VERSION 5.8 ;
BUSBITCHARS "[]" ;
DIVIDERCHAR "/" ;
UNITS
    DATABASE MICRONS 2000 ;
END UNITS

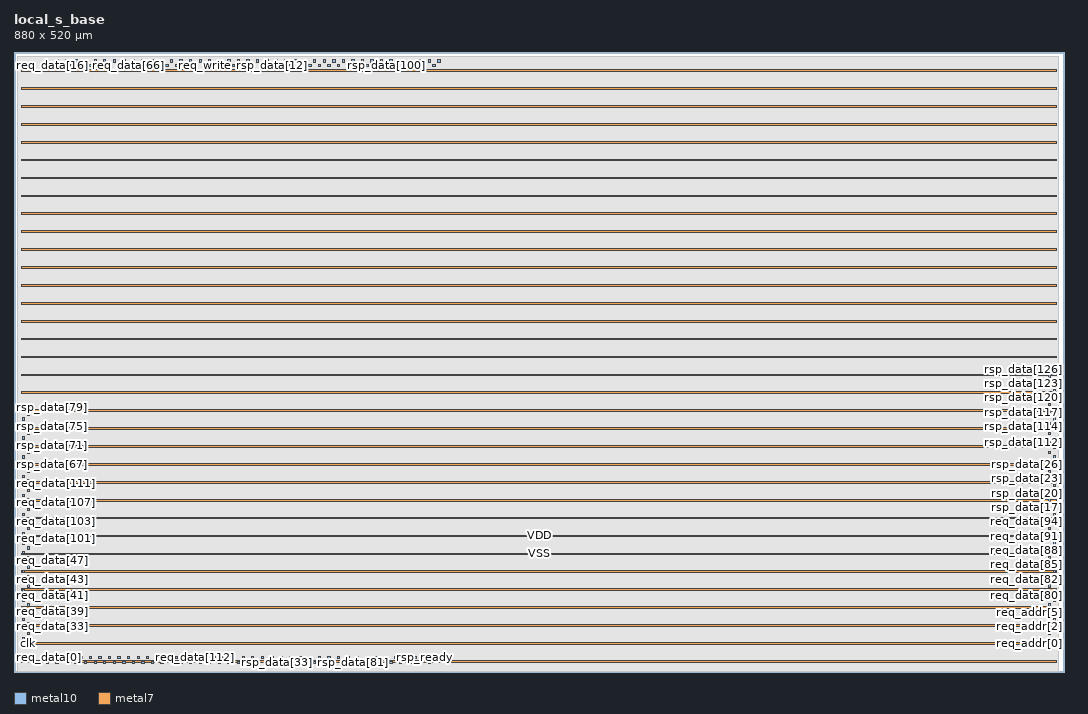
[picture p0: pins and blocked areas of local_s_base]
MACRO local_s_base
  FOREIGN local_s_base 0 0 ;
  CLASS BLOCK ;
  SIZE 880 BY 520 ;
  PIN clk
    DIRECTION INPUT ;
    USE SIGNAL ;
    PORT
      LAYER metal10 ;
        RECT  11.095 23.07 13.095 25.07 ;
    END
  END clk
  PIN req_addr[0]
    DIRECTION INPUT ;
    USE SIGNAL ;
    PORT
      LAYER metal10 ;
        RECT  867.095 23.07 869.095 25.07 ;
    END
  END req_addr[0]
  PIN req_addr[1]
    DIRECTION INPUT ;
    USE SIGNAL ;
    PORT
      LAYER metal10 ;
        RECT  871.095 27.07 873.095 29.07 ;
    END
  END req_addr[1]
  PIN req_addr[2]
    DIRECTION INPUT ;
    USE SIGNAL ;
    PORT
      LAYER metal10 ;
        RECT  867.095 31.07 869.095 33.07 ;
    END
  END req_addr[2]
  PIN req_addr[3]
    DIRECTION INPUT ;
    USE SIGNAL ;
    PORT
      LAYER metal10 ;
        RECT  871.095 35.07 873.095 37.07 ;
    END
  END req_addr[3]
  PIN req_addr[4]
    DIRECTION INPUT ;
    USE SIGNAL ;
    PORT
      LAYER metal10 ;
        RECT  867.095 39.07 869.095 41.07 ;
    END
  END req_addr[4]
  PIN req_addr[5]
    DIRECTION INPUT ;
    USE SIGNAL ;
    PORT
      LAYER metal10 ;
        RECT  871.095 43.07 873.095 45.07 ;
    END
  END req_addr[5]
  PIN req_addr[6]
    DIRECTION INPUT ;
    USE SIGNAL ;
    PORT
      LAYER metal10 ;
        RECT  867.095 47.07 869.095 49.07 ;
    END
  END req_addr[6]
  PIN req_addr[7]
    DIRECTION INPUT ;
    USE SIGNAL ;
    PORT
      LAYER metal10 ;
        RECT  871.095 51.07 873.095 53.07 ;
    END
  END req_addr[7]
  PIN req_addr[8]
    DIRECTION INPUT ;
    USE SIGNAL ;
    PORT
      LAYER metal10 ;
        RECT  867.095 55.07 869.095 57.07 ;
    END
  END req_addr[8]
  PIN req_addr[9]
    DIRECTION INPUT ;
    USE SIGNAL ;
    PORT
      LAYER metal10 ;
        RECT  871.095 59.07 873.095 61.07 ;
    END
  END req_addr[9]
  PIN req_data[0]
    DIRECTION INPUT ;
    USE SIGNAL ;
    PORT
      LAYER metal10 ;
        RECT  23.095 11.07 25.095 13.07 ;
    END
  END req_data[0]
  PIN req_data[100]
    DIRECTION INPUT ;
    USE SIGNAL ;
    PORT
      LAYER metal10 ;
        RECT  7.095 107.07 9.095 109.07 ;
    END
  END req_data[100]
  PIN req_data[101]
    DIRECTION INPUT ;
    USE SIGNAL ;
    PORT
      LAYER metal10 ;
        RECT  11.095 111.07 13.095 113.07 ;
    END
  END req_data[101]
  PIN req_data[102]
    DIRECTION INPUT ;
    USE SIGNAL ;
    PORT
      LAYER metal10 ;
        RECT  7.095 115.07 9.095 117.07 ;
    END
  END req_data[102]
  PIN req_data[103]
    DIRECTION INPUT ;
    USE SIGNAL ;
    PORT
      LAYER metal10 ;
        RECT  11.095 119.07 13.095 121.07 ;
    END
  END req_data[103]
  PIN req_data[104]
    DIRECTION INPUT ;
    USE SIGNAL ;
    PORT
      LAYER metal10 ;
        RECT  7.095 123.07 9.095 125.07 ;
    END
  END req_data[104]
  PIN req_data[105]
    DIRECTION INPUT ;
    USE SIGNAL ;
    PORT
      LAYER metal10 ;
        RECT  11.095 127.07 13.095 129.07 ;
    END
  END req_data[105]
  PIN req_data[106]
    DIRECTION INPUT ;
    USE SIGNAL ;
    PORT
      LAYER metal10 ;
        RECT  7.095 131.07 9.095 133.07 ;
    END
  END req_data[106]
  PIN req_data[107]
    DIRECTION INPUT ;
    USE SIGNAL ;
    PORT
      LAYER metal10 ;
        RECT  11.095 135.07 13.095 137.07 ;
    END
  END req_data[107]
  PIN req_data[108]
    DIRECTION INPUT ;
    USE SIGNAL ;
    PORT
      LAYER metal10 ;
        RECT  7.095 139.07 9.095 141.07 ;
    END
  END req_data[108]
  PIN req_data[109]
    DIRECTION INPUT ;
    USE SIGNAL ;
    PORT
      LAYER metal10 ;
        RECT  11.095 143.07 13.095 145.07 ;
    END
  END req_data[109]
  PIN req_data[10]
    DIRECTION INPUT ;
    USE SIGNAL ;
    PORT
      LAYER metal10 ;
        RECT  63.095 11.07 65.095 13.07 ;
    END
  END req_data[10]
  PIN req_data[110]
    DIRECTION INPUT ;
    USE SIGNAL ;
    PORT
      LAYER metal10 ;
        RECT  7.095 147.07 9.095 149.07 ;
    END
  END req_data[110]
  PIN req_data[111]
    DIRECTION INPUT ;
    USE SIGNAL ;
    PORT
      LAYER metal10 ;
        RECT  11.095 151.07 13.095 153.07 ;
    END
  END req_data[111]
  PIN req_data[112]
    DIRECTION INPUT ;
    USE SIGNAL ;
    PORT
      LAYER metal10 ;
        RECT  151.095 11.07 153.095 13.07 ;
    END
  END req_data[112]
  PIN req_data[113]
    DIRECTION INPUT ;
    USE SIGNAL ;
    PORT
      LAYER metal10 ;
        RECT  155.095 7.07 157.095 9.07 ;
    END
  END req_data[113]
  PIN req_data[114]
    DIRECTION INPUT ;
    USE SIGNAL ;
    PORT
      LAYER metal10 ;
        RECT  159.095 11.07 161.095 13.07 ;
    END
  END req_data[114]
  PIN req_data[115]
    DIRECTION INPUT ;
    USE SIGNAL ;
    PORT
      LAYER metal10 ;
        RECT  163.095 7.07 165.095 9.07 ;
    END
  END req_data[115]
  PIN req_data[116]
    DIRECTION INPUT ;
    USE SIGNAL ;
    PORT
      LAYER metal10 ;
        RECT  167.095 11.07 169.095 13.07 ;
    END
  END req_data[116]
  PIN req_data[117]
    DIRECTION INPUT ;
    USE SIGNAL ;
    PORT
      LAYER metal10 ;
        RECT  171.095 7.07 173.095 9.07 ;
    END
  END req_data[117]
  PIN req_data[118]
    DIRECTION INPUT ;
    USE SIGNAL ;
    PORT
      LAYER metal10 ;
        RECT  175.095 11.07 177.095 13.07 ;
    END
  END req_data[118]
  PIN req_data[119]
    DIRECTION INPUT ;
    USE SIGNAL ;
    PORT
      LAYER metal10 ;
        RECT  179.095 7.07 181.095 9.07 ;
    END
  END req_data[119]
  PIN req_data[11]
    DIRECTION INPUT ;
    USE SIGNAL ;
    PORT
      LAYER metal10 ;
        RECT  67.095 7.07 69.095 9.07 ;
    END
  END req_data[11]
  PIN req_data[120]
    DIRECTION INPUT ;
    USE SIGNAL ;
    PORT
      LAYER metal10 ;
        RECT  183.095 11.07 185.095 13.07 ;
    END
  END req_data[120]
  PIN req_data[121]
    DIRECTION INPUT ;
    USE SIGNAL ;
    PORT
      LAYER metal10 ;
        RECT  187.095 7.07 189.095 9.07 ;
    END
  END req_data[121]
  PIN req_data[122]
    DIRECTION INPUT ;
    USE SIGNAL ;
    PORT
      LAYER metal10 ;
        RECT  191.095 11.07 193.095 13.07 ;
    END
  END req_data[122]
  PIN req_data[123]
    DIRECTION INPUT ;
    USE SIGNAL ;
    PORT
      LAYER metal10 ;
        RECT  195.095 7.07 197.095 9.07 ;
    END
  END req_data[123]
  PIN req_data[124]
    DIRECTION INPUT ;
    USE SIGNAL ;
    PORT
      LAYER metal10 ;
        RECT  199.095 11.07 201.095 13.07 ;
    END
  END req_data[124]
  PIN req_data[125]
    DIRECTION INPUT ;
    USE SIGNAL ;
    PORT
      LAYER metal10 ;
        RECT  203.095 7.07 205.095 9.07 ;
    END
  END req_data[125]
  PIN req_data[126]
    DIRECTION INPUT ;
    USE SIGNAL ;
    PORT
      LAYER metal10 ;
        RECT  207.095 11.07 209.095 13.07 ;
    END
  END req_data[126]
  PIN req_data[127]
    DIRECTION INPUT ;
    USE SIGNAL ;
    PORT
      LAYER metal10 ;
        RECT  211.095 7.07 213.095 9.07 ;
    END
  END req_data[127]
  PIN req_data[12]
    DIRECTION INPUT ;
    USE SIGNAL ;
    PORT
      LAYER metal10 ;
        RECT  71.095 11.07 73.095 13.07 ;
    END
  END req_data[12]
  PIN req_data[13]
    DIRECTION INPUT ;
    USE SIGNAL ;
    PORT
      LAYER metal10 ;
        RECT  75.095 7.07 77.095 9.07 ;
    END
  END req_data[13]
  PIN req_data[14]
    DIRECTION INPUT ;
    USE SIGNAL ;
    PORT
      LAYER metal10 ;
        RECT  79.095 11.07 81.095 13.07 ;
    END
  END req_data[14]
  PIN req_data[15]
    DIRECTION INPUT ;
    USE SIGNAL ;
    PORT
      LAYER metal10 ;
        RECT  83.095 7.07 85.095 9.07 ;
    END
  END req_data[15]
  PIN req_data[16]
    DIRECTION INPUT ;
    USE SIGNAL ;
    PORT
      LAYER metal10 ;
        RECT  23.095 507.07 25.095 509.07 ;
    END
  END req_data[16]
  PIN req_data[17]
    DIRECTION INPUT ;
    USE SIGNAL ;
    PORT
      LAYER metal10 ;
        RECT  27.095 511.07 29.095 513.07 ;
    END
  END req_data[17]
  PIN req_data[18]
    DIRECTION INPUT ;
    USE SIGNAL ;
    PORT
      LAYER metal10 ;
        RECT  31.095 507.07 33.095 509.07 ;
    END
  END req_data[18]
  PIN req_data[19]
    DIRECTION INPUT ;
    USE SIGNAL ;
    PORT
      LAYER metal10 ;
        RECT  35.095 511.07 37.095 513.07 ;
    END
  END req_data[19]
  PIN req_data[1]
    DIRECTION INPUT ;
    USE SIGNAL ;
    PORT
      LAYER metal10 ;
        RECT  27.095 7.07 29.095 9.07 ;
    END
  END req_data[1]
  PIN req_data[20]
    DIRECTION INPUT ;
    USE SIGNAL ;
    PORT
      LAYER metal10 ;
        RECT  39.095 507.07 41.095 509.07 ;
    END
  END req_data[20]
  PIN req_data[21]
    DIRECTION INPUT ;
    USE SIGNAL ;
    PORT
      LAYER metal10 ;
        RECT  43.095 511.07 45.095 513.07 ;
    END
  END req_data[21]
  PIN req_data[22]
    DIRECTION INPUT ;
    USE SIGNAL ;
    PORT
      LAYER metal10 ;
        RECT  47.095 507.07 49.095 509.07 ;
    END
  END req_data[22]
  PIN req_data[23]
    DIRECTION INPUT ;
    USE SIGNAL ;
    PORT
      LAYER metal10 ;
        RECT  51.095 511.07 53.095 513.07 ;
    END
  END req_data[23]
  PIN req_data[24]
    DIRECTION INPUT ;
    USE SIGNAL ;
    PORT
      LAYER metal10 ;
        RECT  55.095 507.07 57.095 509.07 ;
    END
  END req_data[24]
  PIN req_data[25]
    DIRECTION INPUT ;
    USE SIGNAL ;
    PORT
      LAYER metal10 ;
        RECT  59.095 511.07 61.095 513.07 ;
    END
  END req_data[25]
  PIN req_data[26]
    DIRECTION INPUT ;
    USE SIGNAL ;
    PORT
      LAYER metal10 ;
        RECT  63.095 507.07 65.095 509.07 ;
    END
  END req_data[26]
  PIN req_data[27]
    DIRECTION INPUT ;
    USE SIGNAL ;
    PORT
      LAYER metal10 ;
        RECT  67.095 511.07 69.095 513.07 ;
    END
  END req_data[27]
  PIN req_data[28]
    DIRECTION INPUT ;
    USE SIGNAL ;
    PORT
      LAYER metal10 ;
        RECT  71.095 507.07 73.095 509.07 ;
    END
  END req_data[28]
  PIN req_data[29]
    DIRECTION INPUT ;
    USE SIGNAL ;
    PORT
      LAYER metal10 ;
        RECT  75.095 511.07 77.095 513.07 ;
    END
  END req_data[29]
  PIN req_data[2]
    DIRECTION INPUT ;
    USE SIGNAL ;
    PORT
      LAYER metal10 ;
        RECT  31.095 11.07 33.095 13.07 ;
    END
  END req_data[2]
  PIN req_data[30]
    DIRECTION INPUT ;
    USE SIGNAL ;
    PORT
      LAYER metal10 ;
        RECT  79.095 507.07 81.095 509.07 ;
    END
  END req_data[30]
  PIN req_data[31]
    DIRECTION INPUT ;
    USE SIGNAL ;
    PORT
      LAYER metal10 ;
        RECT  83.095 511.07 85.095 513.07 ;
    END
  END req_data[31]
  PIN req_data[32]
    DIRECTION INPUT ;
    USE SIGNAL ;
    PORT
      LAYER metal10 ;
        RECT  7.095 27.07 9.095 29.07 ;
    END
  END req_data[32]
  PIN req_data[33]
    DIRECTION INPUT ;
    USE SIGNAL ;
    PORT
      LAYER metal10 ;
        RECT  11.095 31.07 13.095 33.07 ;
    END
  END req_data[33]
  PIN req_data[34]
    DIRECTION INPUT ;
    USE SIGNAL ;
    PORT
      LAYER metal10 ;
        RECT  7.095 35.07 9.095 37.07 ;
    END
  END req_data[34]
  PIN req_data[35]
    DIRECTION INPUT ;
    USE SIGNAL ;
    PORT
      LAYER metal10 ;
        RECT  11.095 39.07 13.095 41.07 ;
    END
  END req_data[35]
  PIN req_data[36]
    DIRECTION INPUT ;
    USE SIGNAL ;
    PORT
      LAYER metal10 ;
        RECT  7.095 43.07 9.095 45.07 ;
    END
  END req_data[36]
  PIN req_data[37]
    DIRECTION INPUT ;
    USE SIGNAL ;
    PORT
      LAYER metal10 ;
        RECT  11.095 47.07 13.095 49.07 ;
    END
  END req_data[37]
  PIN req_data[38]
    DIRECTION INPUT ;
    USE SIGNAL ;
    PORT
      LAYER metal10 ;
        RECT  7.095 51.07 9.095 53.07 ;
    END
  END req_data[38]
  PIN req_data[39]
    DIRECTION INPUT ;
    USE SIGNAL ;
    PORT
      LAYER metal10 ;
        RECT  11.095 55.07 13.095 57.07 ;
    END
  END req_data[39]
  PIN req_data[3]
    DIRECTION INPUT ;
    USE SIGNAL ;
    PORT
      LAYER metal10 ;
        RECT  35.095 7.07 37.095 9.07 ;
    END
  END req_data[3]
  PIN req_data[40]
    DIRECTION INPUT ;
    USE SIGNAL ;
    PORT
      LAYER metal10 ;
        RECT  7.095 59.07 9.095 61.07 ;
    END
  END req_data[40]
  PIN req_data[41]
    DIRECTION INPUT ;
    USE SIGNAL ;
    PORT
      LAYER metal10 ;
        RECT  11.095 63.07 13.095 65.07 ;
    END
  END req_data[41]
  PIN req_data[42]
    DIRECTION INPUT ;
    USE SIGNAL ;
    PORT
      LAYER metal10 ;
        RECT  7.095 67.07 9.095 69.07 ;
    END
  END req_data[42]
  PIN req_data[43]
    DIRECTION INPUT ;
    USE SIGNAL ;
    PORT
      LAYER metal10 ;
        RECT  11.095 71.07 13.095 73.07 ;
    END
  END req_data[43]
  PIN req_data[44]
    DIRECTION INPUT ;
    USE SIGNAL ;
    PORT
      LAYER metal10 ;
        RECT  7.095 75.07 9.095 77.07 ;
    END
  END req_data[44]
  PIN req_data[45]
    DIRECTION INPUT ;
    USE SIGNAL ;
    PORT
      LAYER metal10 ;
        RECT  11.095 79.07 13.095 81.07 ;
    END
  END req_data[45]
  PIN req_data[46]
    DIRECTION INPUT ;
    USE SIGNAL ;
    PORT
      LAYER metal10 ;
        RECT  7.095 83.07 9.095 85.07 ;
    END
  END req_data[46]
  PIN req_data[47]
    DIRECTION INPUT ;
    USE SIGNAL ;
    PORT
      LAYER metal10 ;
        RECT  11.095 87.07 13.095 89.07 ;
    END
  END req_data[47]
  PIN req_data[48]
    DIRECTION INPUT ;
    USE SIGNAL ;
    PORT
      LAYER metal10 ;
        RECT  87.095 11.07 89.095 13.07 ;
    END
  END req_data[48]
  PIN req_data[49]
    DIRECTION INPUT ;
    USE SIGNAL ;
    PORT
      LAYER metal10 ;
        RECT  91.095 7.07 93.095 9.07 ;
    END
  END req_data[49]
  PIN req_data[4]
    DIRECTION INPUT ;
    USE SIGNAL ;
    PORT
      LAYER metal10 ;
        RECT  39.095 11.07 41.095 13.07 ;
    END
  END req_data[4]
  PIN req_data[50]
    DIRECTION INPUT ;
    USE SIGNAL ;
    PORT
      LAYER metal10 ;
        RECT  95.095 11.07 97.095 13.07 ;
    END
  END req_data[50]
  PIN req_data[51]
    DIRECTION INPUT ;
    USE SIGNAL ;
    PORT
      LAYER metal10 ;
        RECT  99.095 7.07 101.095 9.07 ;
    END
  END req_data[51]
  PIN req_data[52]
    DIRECTION INPUT ;
    USE SIGNAL ;
    PORT
      LAYER metal10 ;
        RECT  103.095 11.07 105.095 13.07 ;
    END
  END req_data[52]
  PIN req_data[53]
    DIRECTION INPUT ;
    USE SIGNAL ;
    PORT
      LAYER metal10 ;
        RECT  107.095 7.07 109.095 9.07 ;
    END
  END req_data[53]
  PIN req_data[54]
    DIRECTION INPUT ;
    USE SIGNAL ;
    PORT
      LAYER metal10 ;
        RECT  111.095 11.07 113.095 13.07 ;
    END
  END req_data[54]
  PIN req_data[55]
    DIRECTION INPUT ;
    USE SIGNAL ;
    PORT
      LAYER metal10 ;
        RECT  115.095 7.07 117.095 9.07 ;
    END
  END req_data[55]
  PIN req_data[56]
    DIRECTION INPUT ;
    USE SIGNAL ;
    PORT
      LAYER metal10 ;
        RECT  119.095 11.07 121.095 13.07 ;
    END
  END req_data[56]
  PIN req_data[57]
    DIRECTION INPUT ;
    USE SIGNAL ;
    PORT
      LAYER metal10 ;
        RECT  123.095 7.07 125.095 9.07 ;
    END
  END req_data[57]
  PIN req_data[58]
    DIRECTION INPUT ;
    USE SIGNAL ;
    PORT
      LAYER metal10 ;
        RECT  127.095 11.07 129.095 13.07 ;
    END
  END req_data[58]
  PIN req_data[59]
    DIRECTION INPUT ;
    USE SIGNAL ;
    PORT
      LAYER metal10 ;
        RECT  131.095 7.07 133.095 9.07 ;
    END
  END req_data[59]
  PIN req_data[5]
    DIRECTION INPUT ;
    USE SIGNAL ;
    PORT
      LAYER metal10 ;
        RECT  43.095 7.07 45.095 9.07 ;
    END
  END req_data[5]
  PIN req_data[60]
    DIRECTION INPUT ;
    USE SIGNAL ;
    PORT
      LAYER metal10 ;
        RECT  135.095 11.07 137.095 13.07 ;
    END
  END req_data[60]
  PIN req_data[61]
    DIRECTION INPUT ;
    USE SIGNAL ;
    PORT
      LAYER metal10 ;
        RECT  139.095 7.07 141.095 9.07 ;
    END
  END req_data[61]
  PIN req_data[62]
    DIRECTION INPUT ;
    USE SIGNAL ;
    PORT
      LAYER metal10 ;
        RECT  143.095 11.07 145.095 13.07 ;
    END
  END req_data[62]
  PIN req_data[63]
    DIRECTION INPUT ;
    USE SIGNAL ;
    PORT
      LAYER metal10 ;
        RECT  147.095 7.07 149.095 9.07 ;
    END
  END req_data[63]
  PIN req_data[64]
    DIRECTION INPUT ;
    USE SIGNAL ;
    PORT
      LAYER metal10 ;
        RECT  87.095 507.07 89.095 509.07 ;
    END
  END req_data[64]
  PIN req_data[65]
    DIRECTION INPUT ;
    USE SIGNAL ;
    PORT
      LAYER metal10 ;
        RECT  91.095 511.07 93.095 513.07 ;
    END
  END req_data[65]
  PIN req_data[66]
    DIRECTION INPUT ;
    USE SIGNAL ;
    PORT
      LAYER metal10 ;
        RECT  95.095 507.07 97.095 509.07 ;
    END
  END req_data[66]
  PIN req_data[67]
    DIRECTION INPUT ;
    USE SIGNAL ;
    PORT
      LAYER metal10 ;
        RECT  99.095 511.07 101.095 513.07 ;
    END
  END req_data[67]
  PIN req_data[68]
    DIRECTION INPUT ;
    USE SIGNAL ;
    PORT
      LAYER metal10 ;
        RECT  103.095 507.07 105.095 509.07 ;
    END
  END req_data[68]
  PIN req_data[69]
    DIRECTION INPUT ;
    USE SIGNAL ;
    PORT
      LAYER metal10 ;
        RECT  107.095 511.07 109.095 513.07 ;
    END
  END req_data[69]
  PIN req_data[6]
    DIRECTION INPUT ;
    USE SIGNAL ;
    PORT
      LAYER metal10 ;
        RECT  47.095 11.07 49.095 13.07 ;
    END
  END req_data[6]
  PIN req_data[70]
    DIRECTION INPUT ;
    USE SIGNAL ;
    PORT
      LAYER metal10 ;
        RECT  111.095 507.07 113.095 509.07 ;
    END
  END req_data[70]
  PIN req_data[71]
    DIRECTION INPUT ;
    USE SIGNAL ;
    PORT
      LAYER metal10 ;
        RECT  115.095 511.07 117.095 513.07 ;
    END
  END req_data[71]
  PIN req_data[72]
    DIRECTION INPUT ;
    USE SIGNAL ;
    PORT
      LAYER metal10 ;
        RECT  119.095 507.07 121.095 509.07 ;
    END
  END req_data[72]
  PIN req_data[73]
    DIRECTION INPUT ;
    USE SIGNAL ;
    PORT
      LAYER metal10 ;
        RECT  123.095 511.07 125.095 513.07 ;
    END
  END req_data[73]
  PIN req_data[74]
    DIRECTION INPUT ;
    USE SIGNAL ;
    PORT
      LAYER metal10 ;
        RECT  127.095 507.07 129.095 509.07 ;
    END
  END req_data[74]
  PIN req_data[75]
    DIRECTION INPUT ;
    USE SIGNAL ;
    PORT
      LAYER metal10 ;
        RECT  131.095 511.07 133.095 513.07 ;
    END
  END req_data[75]
  PIN req_data[76]
    DIRECTION INPUT ;
    USE SIGNAL ;
    PORT
      LAYER metal10 ;
        RECT  135.095 507.07 137.095 509.07 ;
    END
  END req_data[76]
  PIN req_data[77]
    DIRECTION INPUT ;
    USE SIGNAL ;
    PORT
      LAYER metal10 ;
        RECT  139.095 511.07 141.095 513.07 ;
    END
  END req_data[77]
  PIN req_data[78]
    DIRECTION INPUT ;
    USE SIGNAL ;
    PORT
      LAYER metal10 ;
        RECT  143.095 507.07 145.095 509.07 ;
    END
  END req_data[78]
  PIN req_data[79]
    DIRECTION INPUT ;
    USE SIGNAL ;
    PORT
      LAYER metal10 ;
        RECT  147.095 511.07 149.095 513.07 ;
    END
  END req_data[79]
  PIN req_data[7]
    DIRECTION INPUT ;
    USE SIGNAL ;
    PORT
      LAYER metal10 ;
        RECT  51.095 7.07 53.095 9.07 ;
    END
  END req_data[7]
  PIN req_data[80]
    DIRECTION INPUT ;
    USE SIGNAL ;
    PORT
      LAYER metal10 ;
        RECT  867.095 63.07 869.095 65.07 ;
    END
  END req_data[80]
  PIN req_data[81]
    DIRECTION INPUT ;
    USE SIGNAL ;
    PORT
      LAYER metal10 ;
        RECT  871.095 67.07 873.095 69.07 ;
    END
  END req_data[81]
  PIN req_data[82]
    DIRECTION INPUT ;
    USE SIGNAL ;
    PORT
      LAYER metal10 ;
        RECT  867.095 71.07 869.095 73.07 ;
    END
  END req_data[82]
  PIN req_data[83]
    DIRECTION INPUT ;
    USE SIGNAL ;
    PORT
      LAYER metal10 ;
        RECT  871.095 75.07 873.095 77.07 ;
    END
  END req_data[83]
  PIN req_data[84]
    DIRECTION INPUT ;
    USE SIGNAL ;
    PORT
      LAYER metal10 ;
        RECT  867.095 79.07 869.095 81.07 ;
    END
  END req_data[84]
  PIN req_data[85]
    DIRECTION INPUT ;
    USE SIGNAL ;
    PORT
      LAYER metal10 ;
        RECT  871.095 83.07 873.095 85.07 ;
    END
  END req_data[85]
  PIN req_data[86]
    DIRECTION INPUT ;
    USE SIGNAL ;
    PORT
      LAYER metal10 ;
        RECT  867.095 87.07 869.095 89.07 ;
    END
  END req_data[86]
  PIN req_data[87]
    DIRECTION INPUT ;
    USE SIGNAL ;
    PORT
      LAYER metal10 ;
        RECT  871.095 91.07 873.095 93.07 ;
    END
  END req_data[87]
  PIN req_data[88]
    DIRECTION INPUT ;
    USE SIGNAL ;
    PORT
      LAYER metal10 ;
        RECT  867.095 95.07 869.095 97.07 ;
    END
  END req_data[88]
  PIN req_data[89]
    DIRECTION INPUT ;
    USE SIGNAL ;
    PORT
      LAYER metal10 ;
        RECT  871.095 99.07 873.095 101.07 ;
    END
  END req_data[89]
  PIN req_data[8]
    DIRECTION INPUT ;
    USE SIGNAL ;
    PORT
      LAYER metal10 ;
        RECT  55.095 11.07 57.095 13.07 ;
    END
  END req_data[8]
  PIN req_data[90]
    DIRECTION INPUT ;
    USE SIGNAL ;
    PORT
      LAYER metal10 ;
        RECT  867.095 103.07 869.095 105.07 ;
    END
  END req_data[90]
  PIN req_data[91]
    DIRECTION INPUT ;
    USE SIGNAL ;
    PORT
      LAYER metal10 ;
        RECT  871.095 107.07 873.095 109.07 ;
    END
  END req_data[91]
  PIN req_data[92]
    DIRECTION INPUT ;
    USE SIGNAL ;
    PORT
      LAYER metal10 ;
        RECT  867.095 111.07 869.095 113.07 ;
    END
  END req_data[92]
  PIN req_data[93]
    DIRECTION INPUT ;
    USE SIGNAL ;
    PORT
      LAYER metal10 ;
        RECT  871.095 115.07 873.095 117.07 ;
    END
  END req_data[93]
  PIN req_data[94]
    DIRECTION INPUT ;
    USE SIGNAL ;
    PORT
      LAYER metal10 ;
        RECT  867.095 119.07 869.095 121.07 ;
    END
  END req_data[94]
  PIN req_data[95]
    DIRECTION INPUT ;
    USE SIGNAL ;
    PORT
      LAYER metal10 ;
        RECT  871.095 123.07 873.095 125.07 ;
    END
  END req_data[95]
  PIN req_data[96]
    DIRECTION INPUT ;
    USE SIGNAL ;
    PORT
      LAYER metal10 ;
        RECT  7.095 91.07 9.095 93.07 ;
    END
  END req_data[96]
  PIN req_data[97]
    DIRECTION INPUT ;
    USE SIGNAL ;
    PORT
      LAYER metal10 ;
        RECT  11.095 95.07 13.095 97.07 ;
    END
  END req_data[97]
  PIN req_data[98]
    DIRECTION INPUT ;
    USE SIGNAL ;
    PORT
      LAYER metal10 ;
        RECT  7.095 99.07 9.095 101.07 ;
    END
  END req_data[98]
  PIN req_data[99]
    DIRECTION INPUT ;
    USE SIGNAL ;
    PORT
      LAYER metal10 ;
        RECT  11.095 103.07 13.095 105.07 ;
    END
  END req_data[99]
  PIN req_data[9]
    DIRECTION INPUT ;
    USE SIGNAL ;
    PORT
      LAYER metal10 ;
        RECT  59.095 7.07 61.095 9.07 ;
    END
  END req_data[9]
  PIN req_ready
    DIRECTION OUTPUT ;
    USE SIGNAL ;
    PORT
      LAYER metal10 ;
        RECT  151.095 507.07 153.095 509.07 ;
    END
  END req_ready
  PIN req_valid
    DIRECTION INPUT ;
    USE SIGNAL ;
    PORT
      LAYER metal10 ;
        RECT  155.095 511.07 157.095 513.07 ;
    END
  END req_valid
  PIN req_write
    DIRECTION INPUT ;
    USE SIGNAL ;
    PORT
      LAYER metal10 ;
        RECT  159.095 507.07 161.095 509.07 ;
    END
  END req_write
  PIN reset
    DIRECTION INPUT ;
    USE SIGNAL ;
    PORT
      LAYER metal10 ;
        RECT  163.095 511.07 165.095 513.07 ;
    END
  END reset
  PIN rsp_data[0]
    DIRECTION OUTPUT ;
    USE SIGNAL ;
    PORT
      LAYER metal10 ;
        RECT  167.095 507.07 169.095 509.07 ;
    END
  END rsp_data[0]
  PIN rsp_data[100]
    DIRECTION OUTPUT ;
    USE SIGNAL ;
    PORT
      LAYER metal10 ;
        RECT  311.095 507.07 313.095 509.07 ;
    END
  END rsp_data[100]
  PIN rsp_data[101]
    DIRECTION OUTPUT ;
    USE SIGNAL ;
    PORT
      LAYER metal10 ;
        RECT  315.095 511.07 317.095 513.07 ;
    END
  END rsp_data[101]
  PIN rsp_data[102]
    DIRECTION OUTPUT ;
    USE SIGNAL ;
    PORT
      LAYER metal10 ;
        RECT  319.095 507.07 321.095 509.07 ;
    END
  END rsp_data[102]
  PIN rsp_data[103]
    DIRECTION OUTPUT ;
    USE SIGNAL ;
    PORT
      LAYER metal10 ;
        RECT  323.095 511.07 325.095 513.07 ;
    END
  END rsp_data[103]
  PIN rsp_data[104]
    DIRECTION OUTPUT ;
    USE SIGNAL ;
    PORT
      LAYER metal10 ;
        RECT  327.095 507.07 329.095 509.07 ;
    END
  END rsp_data[104]
  PIN rsp_data[105]
    DIRECTION OUTPUT ;
    USE SIGNAL ;
    PORT
      LAYER metal10 ;
        RECT  331.095 511.07 333.095 513.07 ;
    END
  END rsp_data[105]
  PIN rsp_data[106]
    DIRECTION OUTPUT ;
    USE SIGNAL ;
    PORT
      LAYER metal10 ;
        RECT  335.095 507.07 337.095 509.07 ;
    END
  END rsp_data[106]
  PIN rsp_data[107]
    DIRECTION OUTPUT ;
    USE SIGNAL ;
    PORT
      LAYER metal10 ;
        RECT  339.095 511.07 341.095 513.07 ;
    END
  END rsp_data[107]
  PIN rsp_data[108]
    DIRECTION OUTPUT ;
    USE SIGNAL ;
    PORT
      LAYER metal10 ;
        RECT  343.095 507.07 345.095 509.07 ;
    END
  END rsp_data[108]
  PIN rsp_data[109]
    DIRECTION OUTPUT ;
    USE SIGNAL ;
    PORT
      LAYER metal10 ;
        RECT  347.095 511.07 349.095 513.07 ;
    END
  END rsp_data[109]
  PIN rsp_data[10]
    DIRECTION OUTPUT ;
    USE SIGNAL ;
    PORT
      LAYER metal10 ;
        RECT  207.095 507.07 209.095 509.07 ;
    END
  END rsp_data[10]
  PIN rsp_data[110]
    DIRECTION OUTPUT ;
    USE SIGNAL ;
    PORT
      LAYER metal10 ;
        RECT  351.095 507.07 353.095 509.07 ;
    END
  END rsp_data[110]
  PIN rsp_data[111]
    DIRECTION OUTPUT ;
    USE SIGNAL ;
    PORT
      LAYER metal10 ;
        RECT  355.095 511.07 357.095 513.07 ;
    END
  END rsp_data[111]
  PIN rsp_data[112]
    DIRECTION OUTPUT ;
    USE SIGNAL ;
    PORT
      LAYER metal10 ;
        RECT  867.095 191.07 869.095 193.07 ;
    END
  END rsp_data[112]
  PIN rsp_data[113]
    DIRECTION OUTPUT ;
    USE SIGNAL ;
    PORT
      LAYER metal10 ;
        RECT  871.095 195.07 873.095 197.07 ;
    END
  END rsp_data[113]
  PIN rsp_data[114]
    DIRECTION OUTPUT ;
    USE SIGNAL ;
    PORT
      LAYER metal10 ;
        RECT  867.095 199.07 869.095 201.07 ;
    END
  END rsp_data[114]
  PIN rsp_data[115]
    DIRECTION OUTPUT ;
    USE SIGNAL ;
    PORT
      LAYER metal10 ;
        RECT  871.095 203.07 873.095 205.07 ;
    END
  END rsp_data[115]
  PIN rsp_data[116]
    DIRECTION OUTPUT ;
    USE SIGNAL ;
    PORT
      LAYER metal10 ;
        RECT  867.095 207.07 869.095 209.07 ;
    END
  END rsp_data[116]
  PIN rsp_data[117]
    DIRECTION OUTPUT ;
    USE SIGNAL ;
    PORT
      LAYER metal10 ;
        RECT  871.095 211.07 873.095 213.07 ;
    END
  END rsp_data[117]
  PIN rsp_data[118]
    DIRECTION OUTPUT ;
    USE SIGNAL ;
    PORT
      LAYER metal10 ;
        RECT  867.095 215.07 869.095 217.07 ;
    END
  END rsp_data[118]
  PIN rsp_data[119]
    DIRECTION OUTPUT ;
    USE SIGNAL ;
    PORT
      LAYER metal10 ;
        RECT  871.095 219.07 873.095 221.07 ;
    END
  END rsp_data[119]
  PIN rsp_data[11]
    DIRECTION OUTPUT ;
    USE SIGNAL ;
    PORT
      LAYER metal10 ;
        RECT  211.095 511.07 213.095 513.07 ;
    END
  END rsp_data[11]
  PIN rsp_data[120]
    DIRECTION OUTPUT ;
    USE SIGNAL ;
    PORT
      LAYER metal10 ;
        RECT  867.095 223.07 869.095 225.07 ;
    END
  END rsp_data[120]
  PIN rsp_data[121]
    DIRECTION OUTPUT ;
    USE SIGNAL ;
    PORT
      LAYER metal10 ;
        RECT  871.095 227.07 873.095 229.07 ;
    END
  END rsp_data[121]
  PIN rsp_data[122]
    DIRECTION OUTPUT ;
    USE SIGNAL ;
    PORT
      LAYER metal10 ;
        RECT  867.095 231.07 869.095 233.07 ;
    END
  END rsp_data[122]
  PIN rsp_data[123]
    DIRECTION OUTPUT ;
    USE SIGNAL ;
    PORT
      LAYER metal10 ;
        RECT  871.095 235.07 873.095 237.07 ;
    END
  END rsp_data[123]
  PIN rsp_data[124]
    DIRECTION OUTPUT ;
    USE SIGNAL ;
    PORT
      LAYER metal10 ;
        RECT  867.095 239.07 869.095 241.07 ;
    END
  END rsp_data[124]
  PIN rsp_data[125]
    DIRECTION OUTPUT ;
    USE SIGNAL ;
    PORT
      LAYER metal10 ;
        RECT  871.095 243.07 873.095 245.07 ;
    END
  END rsp_data[125]
  PIN rsp_data[126]
    DIRECTION OUTPUT ;
    USE SIGNAL ;
    PORT
      LAYER metal10 ;
        RECT  867.095 247.07 869.095 249.07 ;
    END
  END rsp_data[126]
  PIN rsp_data[127]
    DIRECTION OUTPUT ;
    USE SIGNAL ;
    PORT
      LAYER metal10 ;
        RECT  871.095 251.07 873.095 253.07 ;
    END
  END rsp_data[127]
  PIN rsp_data[12]
    DIRECTION OUTPUT ;
    USE SIGNAL ;
    PORT
      LAYER metal10 ;
        RECT  215.095 507.07 217.095 509.07 ;
    END
  END rsp_data[12]
  PIN rsp_data[13]
    DIRECTION OUTPUT ;
    USE SIGNAL ;
    PORT
      LAYER metal10 ;
        RECT  219.095 511.07 221.095 513.07 ;
    END
  END rsp_data[13]
  PIN rsp_data[14]
    DIRECTION OUTPUT ;
    USE SIGNAL ;
    PORT
      LAYER metal10 ;
        RECT  223.095 507.07 225.095 509.07 ;
    END
  END rsp_data[14]
  PIN rsp_data[15]
    DIRECTION OUTPUT ;
    USE SIGNAL ;
    PORT
      LAYER metal10 ;
        RECT  227.095 511.07 229.095 513.07 ;
    END
  END rsp_data[15]
  PIN rsp_data[16]
    DIRECTION OUTPUT ;
    USE SIGNAL ;
    PORT
      LAYER metal10 ;
        RECT  867.095 127.07 869.095 129.07 ;
    END
  END rsp_data[16]
  PIN rsp_data[17]
    DIRECTION OUTPUT ;
    USE SIGNAL ;
    PORT
      LAYER metal10 ;
        RECT  871.095 131.07 873.095 133.07 ;
    END
  END rsp_data[17]
  PIN rsp_data[18]
    DIRECTION OUTPUT ;
    USE SIGNAL ;
    PORT
      LAYER metal10 ;
        RECT  867.095 135.07 869.095 137.07 ;
    END
  END rsp_data[18]
  PIN rsp_data[19]
    DIRECTION OUTPUT ;
    USE SIGNAL ;
    PORT
      LAYER metal10 ;
        RECT  871.095 139.07 873.095 141.07 ;
    END
  END rsp_data[19]
  PIN rsp_data[1]
    DIRECTION OUTPUT ;
    USE SIGNAL ;
    PORT
      LAYER metal10 ;
        RECT  171.095 511.07 173.095 513.07 ;
    END
  END rsp_data[1]
  PIN rsp_data[20]
    DIRECTION OUTPUT ;
    USE SIGNAL ;
    PORT
      LAYER metal10 ;
        RECT  867.095 143.07 869.095 145.07 ;
    END
  END rsp_data[20]
  PIN rsp_data[21]
    DIRECTION OUTPUT ;
    USE SIGNAL ;
    PORT
      LAYER metal10 ;
        RECT  871.095 147.07 873.095 149.07 ;
    END
  END rsp_data[21]
  PIN rsp_data[22]
    DIRECTION OUTPUT ;
    USE SIGNAL ;
    PORT
      LAYER metal10 ;
        RECT  867.095 151.07 869.095 153.07 ;
    END
  END rsp_data[22]
  PIN rsp_data[23]
    DIRECTION OUTPUT ;
    USE SIGNAL ;
    PORT
      LAYER metal10 ;
        RECT  871.095 155.07 873.095 157.07 ;
    END
  END rsp_data[23]
  PIN rsp_data[24]
    DIRECTION OUTPUT ;
    USE SIGNAL ;
    PORT
      LAYER metal10 ;
        RECT  867.095 159.07 869.095 161.07 ;
    END
  END rsp_data[24]
  PIN rsp_data[25]
    DIRECTION OUTPUT ;
    USE SIGNAL ;
    PORT
      LAYER metal10 ;
        RECT  871.095 163.07 873.095 165.07 ;
    END
  END rsp_data[25]
  PIN rsp_data[26]
    DIRECTION OUTPUT ;
    USE SIGNAL ;
    PORT
      LAYER metal10 ;
        RECT  867.095 167.07 869.095 169.07 ;
    END
  END rsp_data[26]
  PIN rsp_data[27]
    DIRECTION OUTPUT ;
    USE SIGNAL ;
    PORT
      LAYER metal10 ;
        RECT  871.095 171.07 873.095 173.07 ;
    END
  END rsp_data[27]
  PIN rsp_data[28]
    DIRECTION OUTPUT ;
    USE SIGNAL ;
    PORT
      LAYER metal10 ;
        RECT  867.095 175.07 869.095 177.07 ;
    END
  END rsp_data[28]
  PIN rsp_data[29]
    DIRECTION OUTPUT ;
    USE SIGNAL ;
    PORT
      LAYER metal10 ;
        RECT  871.095 179.07 873.095 181.07 ;
    END
  END rsp_data[29]
  PIN rsp_data[2]
    DIRECTION OUTPUT ;
    USE SIGNAL ;
    PORT
      LAYER metal10 ;
        RECT  175.095 507.07 177.095 509.07 ;
    END
  END rsp_data[2]
  PIN rsp_data[30]
    DIRECTION OUTPUT ;
    USE SIGNAL ;
    PORT
      LAYER metal10 ;
        RECT  867.095 183.07 869.095 185.07 ;
    END
  END rsp_data[30]
  PIN rsp_data[31]
    DIRECTION OUTPUT ;
    USE SIGNAL ;
    PORT
      LAYER metal10 ;
        RECT  871.095 187.07 873.095 189.07 ;
    END
  END rsp_data[31]
  PIN rsp_data[32]
    DIRECTION OUTPUT ;
    USE SIGNAL ;
    PORT
      LAYER metal10 ;
        RECT  215.095 11.07 217.095 13.07 ;
    END
  END rsp_data[32]
  PIN rsp_data[33]
    DIRECTION OUTPUT ;
    USE SIGNAL ;
    PORT
      LAYER metal10 ;
        RECT  219.095 7.07 221.095 9.07 ;
    END
  END rsp_data[33]
  PIN rsp_data[34]
    DIRECTION OUTPUT ;
    USE SIGNAL ;
    PORT
      LAYER metal10 ;
        RECT  223.095 11.07 225.095 13.07 ;
    END
  END rsp_data[34]
  PIN rsp_data[35]
    DIRECTION OUTPUT ;
    USE SIGNAL ;
    PORT
      LAYER metal10 ;
        RECT  227.095 7.07 229.095 9.07 ;
    END
  END rsp_data[35]
  PIN rsp_data[36]
    DIRECTION OUTPUT ;
    USE SIGNAL ;
    PORT
      LAYER metal10 ;
        RECT  231.095 11.07 233.095 13.07 ;
    END
  END rsp_data[36]
  PIN rsp_data[37]
    DIRECTION OUTPUT ;
    USE SIGNAL ;
    PORT
      LAYER metal10 ;
        RECT  235.095 7.07 237.095 9.07 ;
    END
  END rsp_data[37]
  PIN rsp_data[38]
    DIRECTION OUTPUT ;
    USE SIGNAL ;
    PORT
      LAYER metal10 ;
        RECT  239.095 11.07 241.095 13.07 ;
    END
  END rsp_data[38]
  PIN rsp_data[39]
    DIRECTION OUTPUT ;
    USE SIGNAL ;
    PORT
      LAYER metal10 ;
        RECT  243.095 7.07 245.095 9.07 ;
    END
  END rsp_data[39]
  PIN rsp_data[3]
    DIRECTION OUTPUT ;
    USE SIGNAL ;
    PORT
      LAYER metal10 ;
        RECT  179.095 511.07 181.095 513.07 ;
    END
  END rsp_data[3]
  PIN rsp_data[40]
    DIRECTION OUTPUT ;
    USE SIGNAL ;
    PORT
      LAYER metal10 ;
        RECT  247.095 11.07 249.095 13.07 ;
    END
  END rsp_data[40]
  PIN rsp_data[41]
    DIRECTION OUTPUT ;
    USE SIGNAL ;
    PORT
      LAYER metal10 ;
        RECT  251.095 7.07 253.095 9.07 ;
    END
  END rsp_data[41]
  PIN rsp_data[42]
    DIRECTION OUTPUT ;
    USE SIGNAL ;
    PORT
      LAYER metal10 ;
        RECT  255.095 11.07 257.095 13.07 ;
    END
  END rsp_data[42]
  PIN rsp_data[43]
    DIRECTION OUTPUT ;
    USE SIGNAL ;
    PORT
      LAYER metal10 ;
        RECT  259.095 7.07 261.095 9.07 ;
    END
  END rsp_data[43]
  PIN rsp_data[44]
    DIRECTION OUTPUT ;
    USE SIGNAL ;
    PORT
      LAYER metal10 ;
        RECT  263.095 11.07 265.095 13.07 ;
    END
  END rsp_data[44]
  PIN rsp_data[45]
    DIRECTION OUTPUT ;
    USE SIGNAL ;
    PORT
      LAYER metal10 ;
        RECT  267.095 7.07 269.095 9.07 ;
    END
  END rsp_data[45]
  PIN rsp_data[46]
    DIRECTION OUTPUT ;
    USE SIGNAL ;
    PORT
      LAYER metal10 ;
        RECT  271.095 11.07 273.095 13.07 ;
    END
  END rsp_data[46]
  PIN rsp_data[47]
    DIRECTION OUTPUT ;
    USE SIGNAL ;
    PORT
      LAYER metal10 ;
        RECT  275.095 7.07 277.095 9.07 ;
    END
  END rsp_data[47]
  PIN rsp_data[48]
    DIRECTION OUTPUT ;
    USE SIGNAL ;
    PORT
      LAYER metal10 ;
        RECT  231.095 507.07 233.095 509.07 ;
    END
  END rsp_data[48]
  PIN rsp_data[49]
    DIRECTION OUTPUT ;
    USE SIGNAL ;
    PORT
      LAYER metal10 ;
        RECT  235.095 511.07 237.095 513.07 ;
    END
  END rsp_data[49]
  PIN rsp_data[4]
    DIRECTION OUTPUT ;
    USE SIGNAL ;
    PORT
      LAYER metal10 ;
        RECT  183.095 507.07 185.095 509.07 ;
    END
  END rsp_data[4]
  PIN rsp_data[50]
    DIRECTION OUTPUT ;
    USE SIGNAL ;
    PORT
      LAYER metal10 ;
        RECT  239.095 507.07 241.095 509.07 ;
    END
  END rsp_data[50]
  PIN rsp_data[51]
    DIRECTION OUTPUT ;
    USE SIGNAL ;
    PORT
      LAYER metal10 ;
        RECT  243.095 511.07 245.095 513.07 ;
    END
  END rsp_data[51]
  PIN rsp_data[52]
    DIRECTION OUTPUT ;
    USE SIGNAL ;
    PORT
      LAYER metal10 ;
        RECT  247.095 507.07 249.095 509.07 ;
    END
  END rsp_data[52]
  PIN rsp_data[53]
    DIRECTION OUTPUT ;
    USE SIGNAL ;
    PORT
      LAYER metal10 ;
        RECT  251.095 511.07 253.095 513.07 ;
    END
  END rsp_data[53]
  PIN rsp_data[54]
    DIRECTION OUTPUT ;
    USE SIGNAL ;
    PORT
      LAYER metal10 ;
        RECT  255.095 507.07 257.095 509.07 ;
    END
  END rsp_data[54]
  PIN rsp_data[55]
    DIRECTION OUTPUT ;
    USE SIGNAL ;
    PORT
      LAYER metal10 ;
        RECT  259.095 511.07 261.095 513.07 ;
    END
  END rsp_data[55]
  PIN rsp_data[56]
    DIRECTION OUTPUT ;
    USE SIGNAL ;
    PORT
      LAYER metal10 ;
        RECT  263.095 507.07 265.095 509.07 ;
    END
  END rsp_data[56]
  PIN rsp_data[57]
    DIRECTION OUTPUT ;
    USE SIGNAL ;
    PORT
      LAYER metal10 ;
        RECT  267.095 511.07 269.095 513.07 ;
    END
  END rsp_data[57]
  PIN rsp_data[58]
    DIRECTION OUTPUT ;
    USE SIGNAL ;
    PORT
      LAYER metal10 ;
        RECT  271.095 507.07 273.095 509.07 ;
    END
  END rsp_data[58]
  PIN rsp_data[59]
    DIRECTION OUTPUT ;
    USE SIGNAL ;
    PORT
      LAYER metal10 ;
        RECT  275.095 511.07 277.095 513.07 ;
    END
  END rsp_data[59]
  PIN rsp_data[5]
    DIRECTION OUTPUT ;
    USE SIGNAL ;
    PORT
      LAYER metal10 ;
        RECT  187.095 511.07 189.095 513.07 ;
    END
  END rsp_data[5]
  PIN rsp_data[60]
    DIRECTION OUTPUT ;
    USE SIGNAL ;
    PORT
      LAYER metal10 ;
        RECT  279.095 507.07 281.095 509.07 ;
    END
  END rsp_data[60]
  PIN rsp_data[61]
    DIRECTION OUTPUT ;
    USE SIGNAL ;
    PORT
      LAYER metal10 ;
        RECT  283.095 511.07 285.095 513.07 ;
    END
  END rsp_data[61]
  PIN rsp_data[62]
    DIRECTION OUTPUT ;
    USE SIGNAL ;
    PORT
      LAYER metal10 ;
        RECT  287.095 507.07 289.095 509.07 ;
    END
  END rsp_data[62]
  PIN rsp_data[63]
    DIRECTION OUTPUT ;
    USE SIGNAL ;
    PORT
      LAYER metal10 ;
        RECT  291.095 511.07 293.095 513.07 ;
    END
  END rsp_data[63]
  PIN rsp_data[64]
    DIRECTION OUTPUT ;
    USE SIGNAL ;
    PORT
      LAYER metal10 ;
        RECT  7.095 155.07 9.095 157.07 ;
    END
  END rsp_data[64]
  PIN rsp_data[65]
    DIRECTION OUTPUT ;
    USE SIGNAL ;
    PORT
      LAYER metal10 ;
        RECT  11.095 159.07 13.095 161.07 ;
    END
  END rsp_data[65]
  PIN rsp_data[66]
    DIRECTION OUTPUT ;
    USE SIGNAL ;
    PORT
      LAYER metal10 ;
        RECT  7.095 163.07 9.095 165.07 ;
    END
  END rsp_data[66]
  PIN rsp_data[67]
    DIRECTION OUTPUT ;
    USE SIGNAL ;
    PORT
      LAYER metal10 ;
        RECT  11.095 167.07 13.095 169.07 ;
    END
  END rsp_data[67]
  PIN rsp_data[68]
    DIRECTION OUTPUT ;
    USE SIGNAL ;
    PORT
      LAYER metal10 ;
        RECT  7.095 171.07 9.095 173.07 ;
    END
  END rsp_data[68]
  PIN rsp_data[69]
    DIRECTION OUTPUT ;
    USE SIGNAL ;
    PORT
      LAYER metal10 ;
        RECT  11.095 175.07 13.095 177.07 ;
    END
  END rsp_data[69]
  PIN rsp_data[6]
    DIRECTION OUTPUT ;
    USE SIGNAL ;
    PORT
      LAYER metal10 ;
        RECT  191.095 507.07 193.095 509.07 ;
    END
  END rsp_data[6]
  PIN rsp_data[70]
    DIRECTION OUTPUT ;
    USE SIGNAL ;
    PORT
      LAYER metal10 ;
        RECT  7.095 179.07 9.095 181.07 ;
    END
  END rsp_data[70]
  PIN rsp_data[71]
    DIRECTION OUTPUT ;
    USE SIGNAL ;
    PORT
      LAYER metal10 ;
        RECT  11.095 183.07 13.095 185.07 ;
    END
  END rsp_data[71]
  PIN rsp_data[72]
    DIRECTION OUTPUT ;
    USE SIGNAL ;
    PORT
      LAYER metal10 ;
        RECT  7.095 187.07 9.095 189.07 ;
    END
  END rsp_data[72]
  PIN rsp_data[73]
    DIRECTION OUTPUT ;
    USE SIGNAL ;
    PORT
      LAYER metal10 ;
        RECT  11.095 191.07 13.095 193.07 ;
    END
  END rsp_data[73]
  PIN rsp_data[74]
    DIRECTION OUTPUT ;
    USE SIGNAL ;
    PORT
      LAYER metal10 ;
        RECT  7.095 195.07 9.095 197.07 ;
    END
  END rsp_data[74]
  PIN rsp_data[75]
    DIRECTION OUTPUT ;
    USE SIGNAL ;
    PORT
      LAYER metal10 ;
        RECT  11.095 199.07 13.095 201.07 ;
    END
  END rsp_data[75]
  PIN rsp_data[76]
    DIRECTION OUTPUT ;
    USE SIGNAL ;
    PORT
      LAYER metal10 ;
        RECT  7.095 203.07 9.095 205.07 ;
    END
  END rsp_data[76]
  PIN rsp_data[77]
    DIRECTION OUTPUT ;
    USE SIGNAL ;
    PORT
      LAYER metal10 ;
        RECT  11.095 207.07 13.095 209.07 ;
    END
  END rsp_data[77]
  PIN rsp_data[78]
    DIRECTION OUTPUT ;
    USE SIGNAL ;
    PORT
      LAYER metal10 ;
        RECT  7.095 211.07 9.095 213.07 ;
    END
  END rsp_data[78]
  PIN rsp_data[79]
    DIRECTION OUTPUT ;
    USE SIGNAL ;
    PORT
      LAYER metal10 ;
        RECT  11.095 215.07 13.095 217.07 ;
    END
  END rsp_data[79]
  PIN rsp_data[7]
    DIRECTION OUTPUT ;
    USE SIGNAL ;
    PORT
      LAYER metal10 ;
        RECT  195.095 511.07 197.095 513.07 ;
    END
  END rsp_data[7]
  PIN rsp_data[80]
    DIRECTION OUTPUT ;
    USE SIGNAL ;
    PORT
      LAYER metal10 ;
        RECT  279.095 11.07 281.095 13.07 ;
    END
  END rsp_data[80]
  PIN rsp_data[81]
    DIRECTION OUTPUT ;
    USE SIGNAL ;
    PORT
      LAYER metal10 ;
        RECT  283.095 7.07 285.095 9.07 ;
    END
  END rsp_data[81]
  PIN rsp_data[82]
    DIRECTION OUTPUT ;
    USE SIGNAL ;
    PORT
      LAYER metal10 ;
        RECT  287.095 11.07 289.095 13.07 ;
    END
  END rsp_data[82]
  PIN rsp_data[83]
    DIRECTION OUTPUT ;
    USE SIGNAL ;
    PORT
      LAYER metal10 ;
        RECT  291.095 7.07 293.095 9.07 ;
    END
  END rsp_data[83]
  PIN rsp_data[84]
    DIRECTION OUTPUT ;
    USE SIGNAL ;
    PORT
      LAYER metal10 ;
        RECT  295.095 11.07 297.095 13.07 ;
    END
  END rsp_data[84]
  PIN rsp_data[85]
    DIRECTION OUTPUT ;
    USE SIGNAL ;
    PORT
      LAYER metal10 ;
        RECT  299.095 7.07 301.095 9.07 ;
    END
  END rsp_data[85]
  PIN rsp_data[86]
    DIRECTION OUTPUT ;
    USE SIGNAL ;
    PORT
      LAYER metal10 ;
        RECT  303.095 11.07 305.095 13.07 ;
    END
  END rsp_data[86]
  PIN rsp_data[87]
    DIRECTION OUTPUT ;
    USE SIGNAL ;
    PORT
      LAYER metal10 ;
        RECT  307.095 7.07 309.095 9.07 ;
    END
  END rsp_data[87]
  PIN rsp_data[88]
    DIRECTION OUTPUT ;
    USE SIGNAL ;
    PORT
      LAYER metal10 ;
        RECT  311.095 11.07 313.095 13.07 ;
    END
  END rsp_data[88]
  PIN rsp_data[89]
    DIRECTION OUTPUT ;
    USE SIGNAL ;
    PORT
      LAYER metal10 ;
        RECT  315.095 7.07 317.095 9.07 ;
    END
  END rsp_data[89]
  PIN rsp_data[8]
    DIRECTION OUTPUT ;
    USE SIGNAL ;
    PORT
      LAYER metal10 ;
        RECT  199.095 507.07 201.095 509.07 ;
    END
  END rsp_data[8]
  PIN rsp_data[90]
    DIRECTION OUTPUT ;
    USE SIGNAL ;
    PORT
      LAYER metal10 ;
        RECT  319.095 11.07 321.095 13.07 ;
    END
  END rsp_data[90]
  PIN rsp_data[91]
    DIRECTION OUTPUT ;
    USE SIGNAL ;
    PORT
      LAYER metal10 ;
        RECT  323.095 7.07 325.095 9.07 ;
    END
  END rsp_data[91]
  PIN rsp_data[92]
    DIRECTION OUTPUT ;
    USE SIGNAL ;
    PORT
      LAYER metal10 ;
        RECT  327.095 11.07 329.095 13.07 ;
    END
  END rsp_data[92]
  PIN rsp_data[93]
    DIRECTION OUTPUT ;
    USE SIGNAL ;
    PORT
      LAYER metal10 ;
        RECT  331.095 7.07 333.095 9.07 ;
    END
  END rsp_data[93]
  PIN rsp_data[94]
    DIRECTION OUTPUT ;
    USE SIGNAL ;
    PORT
      LAYER metal10 ;
        RECT  335.095 11.07 337.095 13.07 ;
    END
  END rsp_data[94]
  PIN rsp_data[95]
    DIRECTION OUTPUT ;
    USE SIGNAL ;
    PORT
      LAYER metal10 ;
        RECT  339.095 7.07 341.095 9.07 ;
    END
  END rsp_data[95]
  PIN rsp_data[96]
    DIRECTION OUTPUT ;
    USE SIGNAL ;
    PORT
      LAYER metal10 ;
        RECT  295.095 507.07 297.095 509.07 ;
    END
  END rsp_data[96]
  PIN rsp_data[97]
    DIRECTION OUTPUT ;
    USE SIGNAL ;
    PORT
      LAYER metal10 ;
        RECT  299.095 511.07 301.095 513.07 ;
    END
  END rsp_data[97]
  PIN rsp_data[98]
    DIRECTION OUTPUT ;
    USE SIGNAL ;
    PORT
      LAYER metal10 ;
        RECT  303.095 507.07 305.095 509.07 ;
    END
  END rsp_data[98]
  PIN rsp_data[99]
    DIRECTION OUTPUT ;
    USE SIGNAL ;
    PORT
      LAYER metal10 ;
        RECT  307.095 511.07 309.095 513.07 ;
    END
  END rsp_data[99]
  PIN rsp_data[9]
    DIRECTION OUTPUT ;
    USE SIGNAL ;
    PORT
      LAYER metal10 ;
        RECT  203.095 511.07 205.095 513.07 ;
    END
  END rsp_data[9]
  PIN rsp_ready
    DIRECTION INPUT ;
    USE SIGNAL ;
    PORT
      LAYER metal10 ;
        RECT  343.095 11.07 345.095 13.07 ;
    END
  END rsp_ready
  PIN rsp_valid
    DIRECTION OUTPUT ;
    USE SIGNAL ;
    PORT
      LAYER metal10 ;
        RECT  347.095 7.07 349.095 9.07 ;
    END
  END rsp_valid
  PIN VDD
    DIRECTION INOUT ;
    USE POWER ;
    PORT
      LAYER metal7 ;
        RECT  6.08 503.3 874 504.7 ;
        RECT  6.08 473.3 874 474.7 ;
        RECT  6.08 443.3 874 444.7 ;
        RECT  6.08 413.3 874 414.7 ;
        RECT  6.08 383.3 874 384.7 ;
        RECT  6.08 353.3 874 354.7 ;
        RECT  6.08 323.3 874 324.7 ;
        RECT  6.08 293.3 874 294.7 ;
        RECT  6.08 263.3 874 264.7 ;
        RECT  6.08 233.3 874 234.7 ;
        RECT  6.08 203.3 874 204.7 ;
        RECT  6.08 173.3 874 174.7 ;
        RECT  6.08 143.3 874 144.7 ;
        RECT  6.08 113.3 874 114.7 ;
        RECT  6.08 83.3 874 84.7 ;
        RECT  6.08 53.3 874 54.7 ;
        RECT  6.08 23.3 874 24.7 ;
    END
  END VDD
  PIN VSS
    DIRECTION INOUT ;
    USE GROUND ;
    PORT
      LAYER metal7 ;
        RECT  6.08 488.3 874 489.7 ;
        RECT  6.08 458.3 874 459.7 ;
        RECT  6.08 428.3 874 429.7 ;
        RECT  6.08 398.3 874 399.7 ;
        RECT  6.08 368.3 874 369.7 ;
        RECT  6.08 338.3 874 339.7 ;
        RECT  6.08 308.3 874 309.7 ;
        RECT  6.08 278.3 874 279.7 ;
        RECT  6.08 248.3 874 249.7 ;
        RECT  6.08 218.3 874 219.7 ;
        RECT  6.08 188.3 874 189.7 ;
        RECT  6.08 158.3 874 159.7 ;
        RECT  6.08 128.3 874 129.7 ;
        RECT  6.08 98.3 874 99.7 ;
        RECT  6.08 68.3 874 69.7 ;
        RECT  6.08 38.3 874 39.7 ;
        RECT  6.08 8.3 874 9.7 ;
    END
  END VSS
  OBS
    LAYER metal1 ;
     RECT  2.895 0.7 875.695 515.67 ;
    LAYER metal2 ;
     RECT  2.895 0.7 875.695 515.67 ;
    LAYER metal3 ;
     RECT  2.895 0.7 875.695 515.67 ;
    LAYER metal4 ;
     RECT  2.895 0.7 875.695 515.67 ;
    LAYER metal5 ;
     RECT  2.895 0.7 875.695 515.67 ;
    LAYER metal6 ;
     RECT  2.895 0.7 875.695 515.67 ;
    LAYER metal7 ;
     RECT  2.895 0.7 875.695 515.67 ;
    LAYER metal8 ;
     RECT  2.895 0.7 875.695 515.67 ;
    LAYER metal9 ;
     RECT  2.895 0.7 875.695 515.67 ;
    LAYER metal10 ;
     RECT  2.895 0.7 875.695 515.67 ;
  END
END local_s_base
END LIBRARY
